VERSION 5.7 ;
  NOWIREEXTENSIONATPIN ON ;
  DIVIDERCHAR "/" ;
  BUSBITCHARS "[]" ;
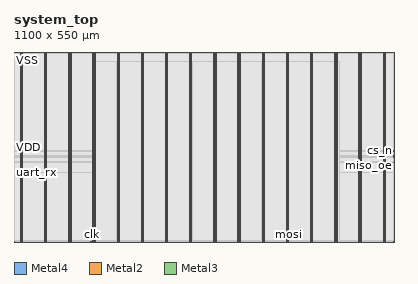
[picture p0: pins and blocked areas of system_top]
MACRO system_top
  CLASS BLOCK ;
  FOREIGN system_top ;
  ORIGIN 0.000 0.000 ;
  SIZE 1100.000 BY 550.000 ;
  PIN VDD
    DIRECTION INOUT ;
    USE POWER ;
    PORT
      LAYER Metal4 ;
        RECT 18.180 0.000 21.180 550.000 ;
    END
    PORT
      LAYER Metal4 ;
        RECT 88.180 0.000 91.180 550.000 ;
    END
    PORT
      LAYER Metal4 ;
        RECT 158.180 0.000 161.180 550.000 ;
    END
    PORT
      LAYER Metal4 ;
        RECT 228.180 0.000 231.180 550.000 ;
    END
    PORT
      LAYER Metal4 ;
        RECT 298.180 0.000 301.180 550.000 ;
    END
    PORT
      LAYER Metal4 ;
        RECT 368.180 0.000 371.180 550.000 ;
    END
    PORT
      LAYER Metal4 ;
        RECT 438.180 0.000 441.180 550.000 ;
    END
    PORT
      LAYER Metal4 ;
        RECT 508.180 0.000 511.180 550.000 ;
    END
    PORT
      LAYER Metal4 ;
        RECT 578.180 0.000 581.180 550.000 ;
    END
    PORT
      LAYER Metal4 ;
        RECT 648.180 0.000 651.180 550.000 ;
    END
    PORT
      LAYER Metal4 ;
        RECT 718.180 0.000 721.180 550.000 ;
    END
    PORT
      LAYER Metal4 ;
        RECT 788.180 0.000 791.180 550.000 ;
    END
    PORT
      LAYER Metal4 ;
        RECT 858.180 0.000 861.180 550.000 ;
    END
    PORT
      LAYER Metal4 ;
        RECT 928.180 0.000 931.180 550.000 ;
    END
    PORT
      LAYER Metal4 ;
        RECT 998.180 0.000 1001.180 550.000 ;
    END
    PORT
      LAYER Metal4 ;
        RECT 1068.180 0.000 1071.180 550.000 ;
    END
  END VDD
  PIN VSS
    DIRECTION INOUT ;
    USE GROUND ;
    PORT
      LAYER Metal4 ;
        RECT 22.180 0.000 25.180 550.000 ;
    END
    PORT
      LAYER Metal4 ;
        RECT 92.180 0.000 95.180 550.000 ;
    END
    PORT
      LAYER Metal4 ;
        RECT 162.180 0.000 165.180 550.000 ;
    END
    PORT
      LAYER Metal4 ;
        RECT 232.180 0.000 235.180 550.000 ;
    END
    PORT
      LAYER Metal4 ;
        RECT 302.180 0.000 305.180 550.000 ;
    END
    PORT
      LAYER Metal4 ;
        RECT 372.180 0.000 375.180 550.000 ;
    END
    PORT
      LAYER Metal4 ;
        RECT 442.180 0.000 445.180 550.000 ;
    END
    PORT
      LAYER Metal4 ;
        RECT 512.180 0.000 515.180 550.000 ;
    END
    PORT
      LAYER Metal4 ;
        RECT 582.180 0.000 585.180 550.000 ;
    END
    PORT
      LAYER Metal4 ;
        RECT 652.180 0.000 655.180 550.000 ;
    END
    PORT
      LAYER Metal4 ;
        RECT 722.180 0.000 725.180 550.000 ;
    END
    PORT
      LAYER Metal4 ;
        RECT 792.180 0.000 795.180 550.000 ;
    END
    PORT
      LAYER Metal4 ;
        RECT 862.180 0.000 865.180 550.000 ;
    END
    PORT
      LAYER Metal4 ;
        RECT 932.180 0.000 935.180 550.000 ;
    END
    PORT
      LAYER Metal4 ;
        RECT 1002.180 0.000 1005.180 550.000 ;
    END
    PORT
      LAYER Metal4 ;
        RECT 1072.180 0.000 1075.180 550.000 ;
    END
  END VSS
  PIN clk
    DIRECTION INPUT ;
    USE SIGNAL ;
    ANTENNAGATEAREA 4.738000 ;
    ANTENNADIFFAREA 0.410400 ;
    PORT
      LAYER Metal2 ;
        RECT 225.120 0.000 225.680 0.560 ;
    END
  END clk
  PIN cs_n
    DIRECTION INPUT ;
    USE SIGNAL ;
    ANTENNAGATEAREA 0.396000 ;
    ANTENNADIFFAREA 0.410400 ;
    PORT
      LAYER Metal3 ;
        RECT 1099.440 263.200 1100.000 263.760 ;
    END
  END cs_n
  PIN miso
    DIRECTION OUTPUT ;
    USE SIGNAL ;
    ANTENNADIFFAREA 0.897600 ;
    PORT
      LAYER Metal3 ;
        RECT 1099.440 248.640 1100.000 249.200 ;
    END
  END miso
  PIN miso_oe
    DIRECTION OUTPUT ;
    USE SIGNAL ;
    ANTENNADIFFAREA 0.897600 ;
    PORT
      LAYER Metal3 ;
        RECT 1099.440 245.280 1100.000 245.840 ;
    END
  END miso_oe
  PIN mosi
    DIRECTION INPUT ;
    USE SIGNAL ;
    ANTENNAGATEAREA 0.396000 ;
    ANTENNADIFFAREA 0.410400 ;
    PORT
      LAYER Metal2 ;
        RECT 795.200 0.000 795.760 0.560 ;
    END
  END mosi
  PIN rst_n
    DIRECTION INPUT ;
    USE SIGNAL ;
    ANTENNAGATEAREA 0.396000 ;
    ANTENNADIFFAREA 0.410400 ;
    PORT
      LAYER Metal2 ;
        RECT 220.640 0.000 221.200 0.560 ;
    END
  END rst_n
  PIN sck
    DIRECTION INPUT ;
    USE SIGNAL ;
    ANTENNAGATEAREA 0.396000 ;
    ANTENNADIFFAREA 0.410400 ;
    PORT
      LAYER Metal3 ;
        RECT 1099.440 230.720 1100.000 231.280 ;
    END
  END sck
  PIN uart_rx
    DIRECTION INPUT ;
    USE SIGNAL ;
    ANTENNAGATEAREA 0.396000 ;
    ANTENNADIFFAREA 0.410400 ;
    PORT
      LAYER Metal3 ;
        RECT 0.000 201.600 0.560 202.160 ;
    END
  END uart_rx
  OBS
      LAYER Nwell ;
        RECT 2.930 3.490 1096.910 545.310 ;
      LAYER Metal1 ;
        RECT 3.360 3.620 1096.480 545.180 ;
      LAYER Metal2 ;
        RECT 5.180 0.860 1095.220 545.070 ;
        RECT 5.180 0.560 220.340 0.860 ;
        RECT 221.500 0.560 224.820 0.860 ;
        RECT 225.980 0.560 794.900 0.860 ;
        RECT 796.060 0.560 1095.220 0.860 ;
      LAYER Metal3 ;
        RECT 0.560 264.060 1099.440 545.020 ;
        RECT 0.560 262.900 1099.140 264.060 ;
        RECT 0.560 249.500 1099.440 262.900 ;
        RECT 0.560 248.340 1099.140 249.500 ;
        RECT 0.560 246.140 1099.440 248.340 ;
        RECT 0.560 244.980 1099.140 246.140 ;
        RECT 0.560 231.580 1099.440 244.980 ;
        RECT 0.560 230.420 1099.140 231.580 ;
        RECT 0.560 202.460 1099.440 230.420 ;
        RECT 0.860 201.300 1099.440 202.460 ;
        RECT 0.560 3.780 1099.440 201.300 ;
      LAYER Metal4 ;
        RECT 226.940 5.130 227.880 521.270 ;
        RECT 231.480 5.130 231.880 521.270 ;
        RECT 235.480 5.130 297.880 521.270 ;
        RECT 301.480 5.130 301.880 521.270 ;
        RECT 305.480 5.130 367.880 521.270 ;
        RECT 371.480 5.130 371.880 521.270 ;
        RECT 375.480 5.130 437.880 521.270 ;
        RECT 441.480 5.130 441.880 521.270 ;
        RECT 445.480 5.130 507.880 521.270 ;
        RECT 511.480 5.130 511.880 521.270 ;
        RECT 515.480 5.130 577.880 521.270 ;
        RECT 581.480 5.130 581.880 521.270 ;
        RECT 585.480 5.130 647.880 521.270 ;
        RECT 651.480 5.130 651.880 521.270 ;
        RECT 655.480 5.130 717.880 521.270 ;
        RECT 721.480 5.130 721.880 521.270 ;
        RECT 725.480 5.130 787.880 521.270 ;
        RECT 791.480 5.130 791.880 521.270 ;
        RECT 795.480 5.130 857.880 521.270 ;
        RECT 861.480 5.130 861.880 521.270 ;
        RECT 865.480 5.130 927.880 521.270 ;
        RECT 931.480 5.130 931.880 521.270 ;
        RECT 935.480 5.130 942.900 521.270 ;
  END
END system_top
END LIBRARY

